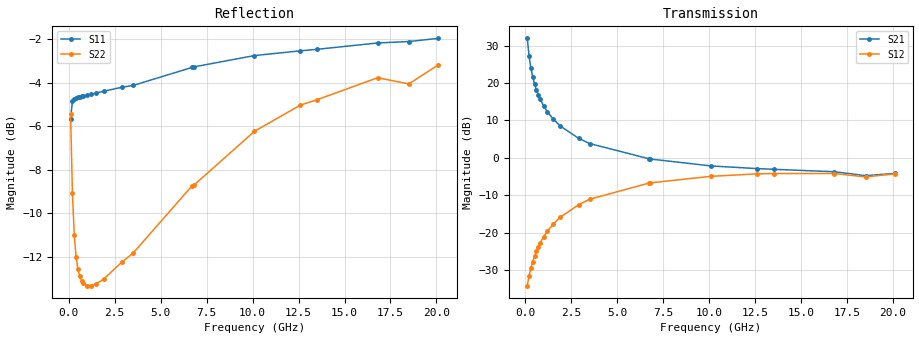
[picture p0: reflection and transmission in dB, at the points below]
!  Infineon Technologies AG
! BFR380L3 , PF131585-7, No.6, Th 09.10.01, soldered on pcb-board, measured with PP GSG850
!  Vce=1.0 V,  Ic=50.0 mA
! Common Emitter S-Parameters:  15. November 2001
#  GHz  S  MA  R  50
! f  S11  S21  S12  S22
! GHz  Mag  Ang  Mag  Ang  Mag  Ang  Mag  Ang
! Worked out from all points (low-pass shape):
!   201 points, 100 MHz to 20.1 GHz, reference 50 ohm
!   highest |S21| = 31.91 dB at 100 MHz (marker M1); lowest = -4.8 dB at 18.5 GHz (marker M2)
!   |S21| within 3 dB of the highest: start of sweep to 163.1 MHz
!   lowest |S11| = -5.7 dB at 100 MHz (marker M3), VSWR 3.18, Z = 20.2 - j24.8 ohm
!   |S11| at or under -10 dB: nowhere
!   |S22| runs from -13.3 to -3.2 dB; largest |S21 - S12| = 39
!   S11 on the Smith chart (normalised r, x): 100 MHz: 0.40, -0.50; 500 MHz: 0.26, -0.05; 2.9 GHz: 0.26, +0.32; 6.7 GHz: 0.31, +0.79; 12.6 GHz: 0.51, +1.53; 20.1 GHz: 0.96, +2.59
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0.1  0.5215 -120.7  39.39 124.2  0.01949 54.8  0.5354 -72.1
0.2  0.5711 -150.0  22.78 106.7  0.0265 56.2  0.351 -103.1
0.3  0.5771 -161.9  15.72 99.1  0.03355 60.4  0.2814 -120.7
0.4  0.5814 -168.7  11.95 94.3  0.04088 63.4  0.2509 -132.5
0.5  0.5832 -173.4  9.623 90.8  0.04863 65.8  0.2351 -140.9
0.6  0.585 -177.0  8.05 88.1  0.05651 67.4  0.2261 -147.1
0.7  0.5871 179.8  6.933 85.6  0.06447 68.4  0.2212 -152.0
0.8  0.588 177.2  6.083 83.3  0.07253 68.9  0.218 -155.9
1  0.5908 172.7  4.897 79.4  0.08853 69.2  0.2153 -161.9
1.2  0.5929 168.7  4.103 75.8  0.1044 69.0  0.2154 -166.3
1.5  0.5971 163.3  3.313 70.8  0.1287 67.8  0.2174 -171.4
1.9  0.6027 156.8  2.653 64.7  0.1606 65.6  0.223 -176.6
2.9  0.6157 142.3  1.813 50.7  0.2357 58.6  0.2442 172.8
3.5  0.6215 134.2  1.546 43.1  0.2789 54.0  0.2557 168.0
6.7  0.6835 99.9  0.972 12.3  0.4569 29.7  0.365 139.1
6.8  0.6855 99.0  0.9611 11.4  0.462 28.9  0.3664 138.1
10.1  0.728 75.3  0.7768 -8.4  0.5645 7.3  0.4874 113.4
12.6  0.7465 62.4  0.7158 -19.9  0.6087 -7.4  0.5601 95.6
13.5  0.7524 58.6  0.7006 -24.0  0.6154 -12.4  0.5761 90.3
16.8  0.7782 46.7  0.6502 -35.3  0.6153 -27.3  0.6473 72.1
18.5  0.7841 44.8  0.5757 -42.2  0.5542 -35.5  0.6265 67.5
20.1  0.7974 38.0  0.6184 -45.6  0.6083 -40.3  0.693 57.5
